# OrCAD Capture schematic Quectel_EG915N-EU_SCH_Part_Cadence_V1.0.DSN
size A1

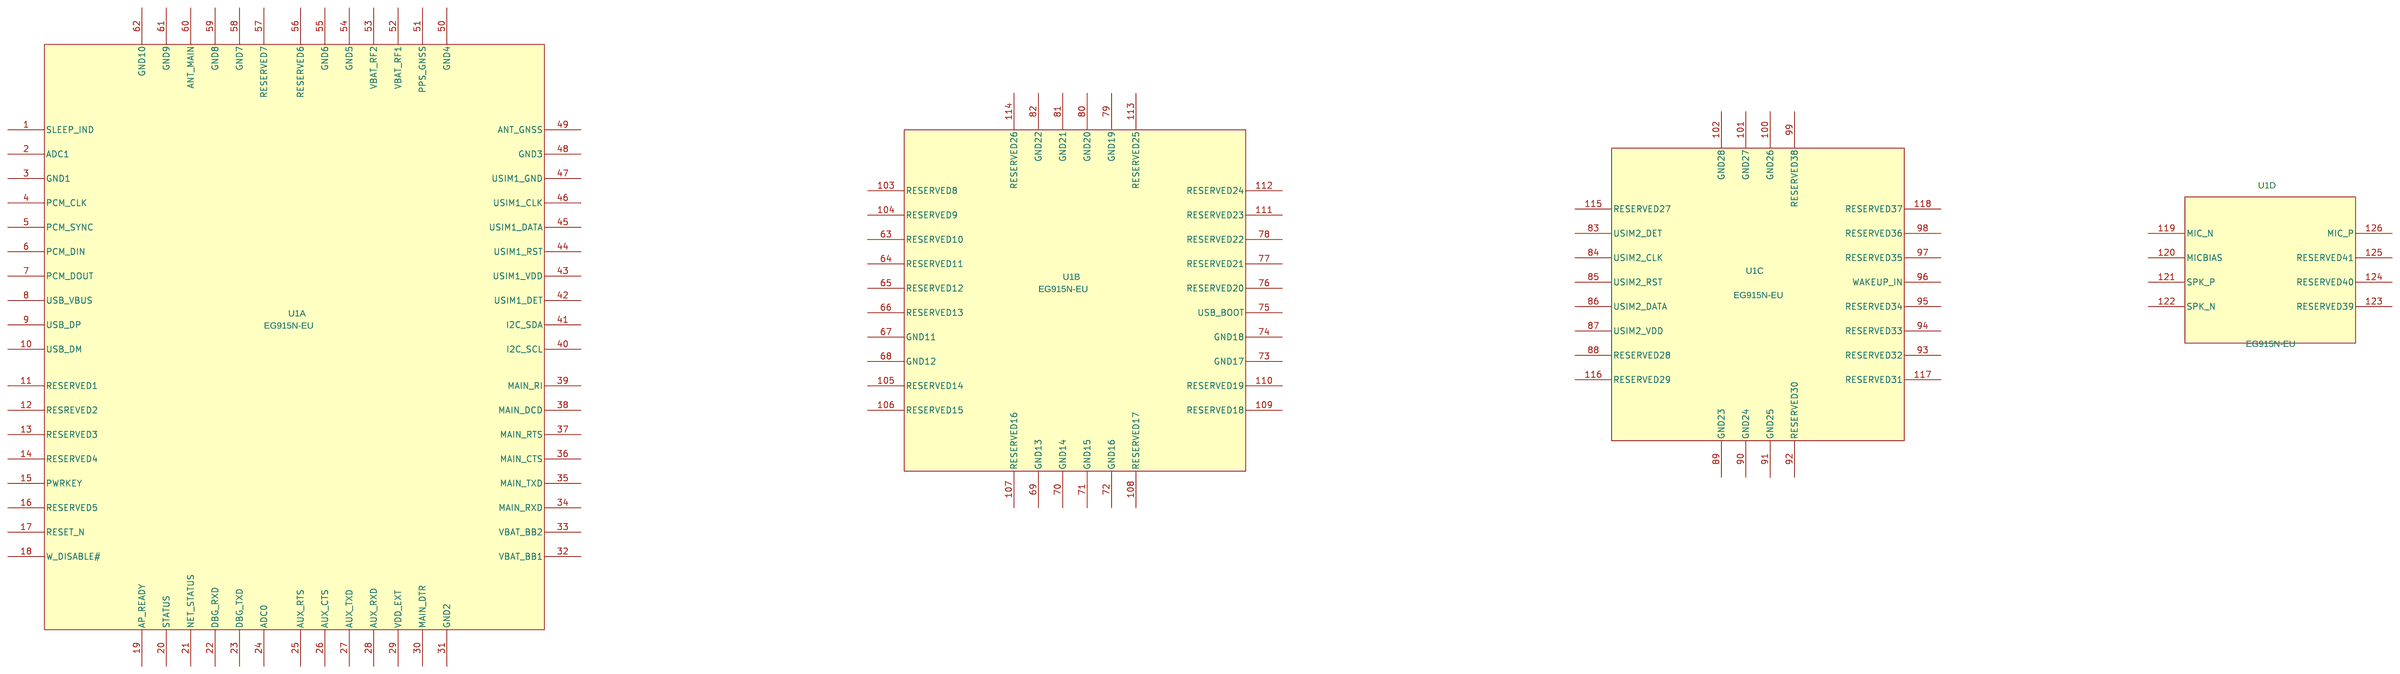
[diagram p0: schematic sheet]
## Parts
U1  EG915N-EU  [EG915N-EU]  (sections A,B,C,D)

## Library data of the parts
U1 = EG915N-EU

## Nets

Not connected (* = marked no-connect by the designer): U1 1(SLEEP_IND) 2(ADC1) 3(GND1) 4(PCM_CLK) 5(PCM_SYNC) 6(PCM_DIN) 7(PCM_DOUT) 8(USB_VBUS) 9(USB_DP) 10(USB_DM) 11(RESERVED1) 12(RESREVED2) 13(RESERVED3) 14(RESERVED4) 15(PWRKEY) 16(RESERVED5) 17(RESET_N) 18(W_DISABLE#) 19(AP_READY) 20(STATUS) 21(NET_STATUS) 22(DBG_RXD) 23(DBG_TXD) 24(ADC0) 25(AUX_RTS) 26(AUX_CTS) 27(AUX_TXD) 28(AUX_RXD) 29(VDD_EXT) 30(MAIN_DTR) 31(GND2) 32(VBAT_BB1) 33(VBAT_BB2) 34(MAIN_RXD) 35(MAIN_TXD) 36(MAIN_CTS) 37(MAIN_RTS) 38(MAIN_DCD) 39(MAIN_RI) 40(I2C_SCL) 41(I2C_SDA) 42(USIM1_DET) 43(USIM1_VDD) 44(USIM1_RST) 45(USIM1_DATA) 46(USIM1_CLK) 47(USIM1_GND) 48(GND3) 49(ANT_GNSS) 50(GND4) 51(PPS_GNSS) 52(VBAT_RF1) 53(VBAT_RF2) 54(GND5) 55(GND6) 56(RESERVED6) 57(RESERVED7) 58(GND7) 59(GND8) 60(ANT_MAIN) 61(GND9) 62(GND10) 63(RESERVED10) 64(RESERVED11) 65(RESERVED12) 66(RESERVED13) 67(GND11) 68(GND12) 69(GND13) 70(GND14) 71(GND15) 72(GND16) 73(GND17) 74(GND18) 75(USB_BOOT) 76(RESERVED20) 77(RESERVED21) 78(RESERVED22) 79(GND19) 80(GND20) 81(GND21) 82(GND22) 83(USIM2_DET) 84(USIM2_CLK) 85(USIM2_RST) 86(USIM2_DATA) 87(USIM2_VDD) 88(RESERVED28) 89(GND23) 90(GND24) 91(GND25) 92(RESERVED30) 93(RESERVED32) 94(RESERVED33) 95(RESERVED34) 96(WAKEUP_IN) 97(RESERVED35) 98(RESERVED36) 99(RESERVED38) 100(GND26) 101(GND27) 102(GND28) 103(RESERVED8) 104(RESERVED9) 105(RESERVED14) 106(RESERVED15) 107(RESERVED16) 108(RESERVED17) 109(RESERVED18) 110(RESERVED19) 111(RESERVED23) 112(RESERVED24) 113(RESERVED25) 114(RESERVED26) 115(RESERVED27) 116(RESERVED29) 117(RESERVED31) 118(RESERVED37) 119(MIC_N) 120(MICBIAS) 121(SPK_P) 122(SPK_N) 123(RESERVED39) 124(RESERVED40) 125(RESERVED41) 126(MIC_P)
